VERSION 5.8 ;
BUSBITCHARS "[]" ;
DIVIDERCHAR "/" ;
UNITS
  DATABASE MICRONS 1000 ;
END UNITS
MANUFACTURINGGRID 0.005 ;

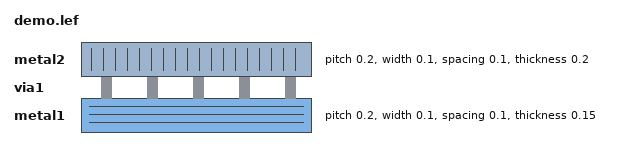
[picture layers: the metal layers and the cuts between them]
LAYER metal1
  TYPE ROUTING ;
  DIRECTION HORIZONTAL ;
  PITCH 0.2 ;
  WIDTH 0.1 ;
  SPACING 0.1 ;
  RESISTANCE RPERSQ 0.4 ;
  CAPACITANCE CPERSQDIST 0.00008 ;
  EDGECAPACITANCE 0.00004 ;
  THICKNESS 0.15 ;
  HEIGHT 0.4 ;
END metal1

LAYER via1
  TYPE CUT ;
  RESISTANCE 6 ;
END via1

LAYER metal2
  TYPE ROUTING ;
  DIRECTION VERTICAL ;
  PITCH 0.2 ;
  WIDTH 0.1 ;
  SPACING 0.1 ;
  RESISTANCE RPERSQ 0.3 ;
  THICKNESS 0.2 ;
  HEIGHT 0.75 ;
END metal2

VIA via1_0 DEFAULT
  LAYER metal1 ;
    RECT -0.07 -0.05 0.07 0.05 ;
  LAYER via1 ;
    RECT -0.035 -0.035 0.035 0.035 ;
  LAYER metal2 ;
    RECT -0.05 -0.07 0.05 0.07 ;
END via1_0

SITE core
  CLASS CORE ;
  SIZE 0.2 BY 1.4 ;
END core

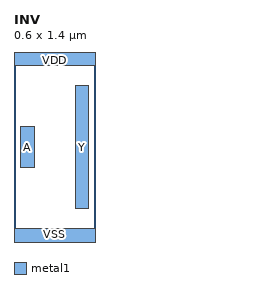
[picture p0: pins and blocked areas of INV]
MACRO INV
  CLASS CORE ;
  ORIGIN 0 0 ;
  SIZE 0.6 BY 1.4 ;
  SITE core ;
  PIN A
    DIRECTION INPUT ;
    PORT
      LAYER metal1 ;
        RECT 0.05 0.55 0.15 0.85 ;
    END
  END A
  PIN Y
    DIRECTION OUTPUT ;
    PORT
      LAYER metal1 ;
        RECT 0.45 0.25 0.55 1.15 ;
    END
  END Y
  PIN VDD
    DIRECTION INOUT ;
    USE POWER ;
    PORT
      LAYER metal1 ;
        RECT 0 1.3 0.6 1.4 ;
    END
  END VDD
  PIN VSS
    DIRECTION INOUT ;
    USE GROUND ;
    PORT
      LAYER metal1 ;
        RECT 0 0 0.6 0.1 ;
    END
  END VSS
END INV

END LIBRARY
